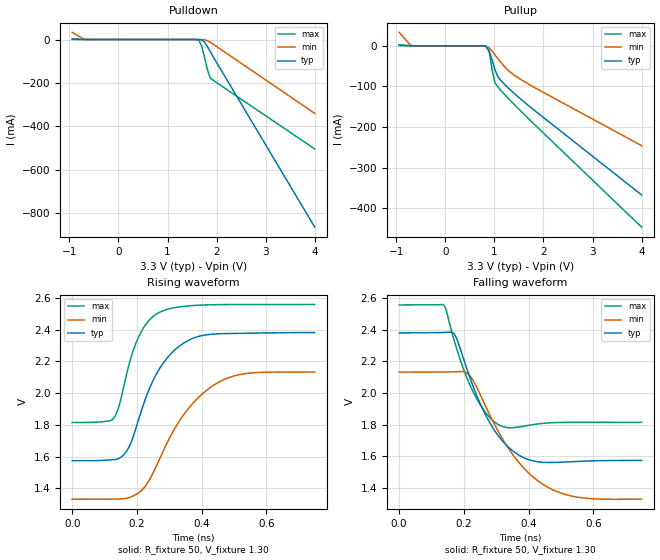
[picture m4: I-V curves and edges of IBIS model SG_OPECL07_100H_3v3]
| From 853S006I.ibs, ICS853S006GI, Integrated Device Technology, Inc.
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[Model] SG_OPECL07_100H_3v3
Model_type   Output_ECL
Polarity   Non-Inverting
|   typ   min   max
C_comp   2pF   1.5pF   2.5pF
Vmeas = 2.0V
Rref = 50
Cref = 0
Vref = 1.3V
|   typ   min   max
[Voltage range]   3.3V   3.135V   3.465V
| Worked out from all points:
|   rising waveform, R_fixture 50, V_fixture 1.30: 20-80 % time 103ps typ, 142ps min, 69.2ps max; typ from 1.57 V to 2.38 V
|   falling waveform, R_fixture 50, V_fixture 1.30: 20-80 % time 106ps typ, 148ps min, 80.1ps max; typ from 2.38 V to 1.57 V
[Pulldown]
|Voltage   I (typ)   I (min)   I (max)
-941.5mV  2.604mA    33.15mA    41.3uA
-711.7mV  75.61uA    1.458mA    617.8nA
-654.2mV  8.078uA    226.5uA    35.41nA
1.587V    -35.94uA   -8.024uA   -361.8uA
1.644V    -319.1uA   -49.68uA   -5.269mA
1.702V    -2.559mA   -299.7uA   -35.21mA
1.759V    -13.03mA   -1.595mA   -87.58mA
1.817V    -33.44mA   -5.834mA   -142.5mA
1.874V    -56.95mA   -13.21mA   -177.7mA
4V        -864.8mA   -340.5mA   -504.4mA
[Pullup]
|Voltage   I (typ)   I (min)   I (max)
-941.5mV  2.604mA    33.15mA    41.3uA
-711.7mV  75.61uA    1.458mA    617.8nA
-654.2mV  8.078uA    226.5uA    35.4nA
839.7mV   -3.036mA   -1.503mA   -1.469mA
897.2mV   -14.72mA   -5.72mA    -16.07mA
954.6mV   -36.13mA   -13.37mA   -60.49mA
1.012V    -59.55mA   -22.45mA   -91.49mA
1.07V     -75.46mA   -31.59mA   -101.1mA
1.127V    -84.8mA    -40.3mA    -109.3mA
1.357V    -112.3mA   -68.13mA   -138.8mA
1.644V    -142.1mA   -90.7mA    -173.4mA
4V        -367.2mA   -245.9mA   -446.5mA
[Ramp]
|   typ   min   max
dV/dt_r   0.646/0.16n   0.641/0.214n   0.595/0.111n
dV/dt_f   0.661/0.16n   0.648/0.22n   0.625/0.123n
R_load =   50.0000
[Rising Waveform]
R_fixture = 50
V_fixture = 1.30   | VCC_typ - 2V
V_fixture_max = 1.465   | VCC_max - 2V
V_fixture_min = 1.135   | VCC_min - 2V
C_fixture = 0.0p
| Time   typ   min   max
0s        1.573V     1.331V     1.814V
122.4ps   1.579V     1.331V     1.831V
140.4ps   1.585V     1.332V     1.893V
159.2ps   1.612V     1.334V     2.042V
207.2ps   1.848V     1.374V     2.364V
271.8ps   2.161V     1.594V     2.511V
354.4ps   2.327V     1.891V     2.549V
452.7ps   2.373V     2.068V     2.557V
545.8ps   2.377V     2.125V     2.558V
749.2ps   2.381V     2.132V     2.558V
[Falling Waveform]
R_fixture = 50
V_fixture = 1.30   | VCC_typ - 2V
V_fixture_max = 1.465   | VCC_max - 2V
V_fixture_min = 1.135   | VCC_min - 2V
C_fixture = 0.0p
| Time   typ   min   max
0s        2.381V     2.133V     2.558V
137.4ps   2.384V     2.133V     2.558V
168.9ps   2.377V     2.134V     2.341V
220.7ps   2.085V     2.103V     2.041V
266.5ps   1.863V     1.919V     1.877V
311.6ps   1.715V     1.737V     1.794V
385.1ps   1.59V      1.524V     1.79V
476.7ps   1.56V      1.385V     1.812V
575.1ps   1.569V     1.333V     1.814V
749.2ps   1.573V     1.327V     1.814V
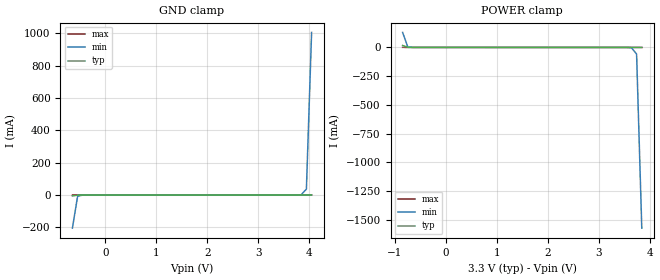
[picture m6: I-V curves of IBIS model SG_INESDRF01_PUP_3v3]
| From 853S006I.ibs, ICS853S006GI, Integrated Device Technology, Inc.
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[Model] SG_INESDRF01_PUP_3v3
Model_type   Input
Polarity   Non-Inverting
Vinl = 0.8V
Vinh = 2.0V
|   typ   min   max
C_comp   2pF   1.5pF   2.5pF
|   typ   min   max
[Voltage range]  3.3V   3.135V   3.465V
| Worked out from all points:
|   GND clamp passes 1 mA (typ) near -0.56 V on its own axis
|   POWER clamp passes 1 mA (typ) near -0.75 V on its own axis
[GND_clamp]
|Voltage   I(Typ)   I(Min)   I(Max)
-646.4mV  -5.84mA    -204.9mA   -106.2uA
-544.3mV  -195.2uA   -7.586mA   -84.59uA
-442.3mV  -85uA      -357.4uA   -80.69uA
3.844V    87.13uA    1.444mA    78.35uA
3.946V    97.02uA    36.95mA    82.14uA
4.048V    411.2uA    1.006A     85.93uA
[POWER_clamp]
|Voltage   I(Typ)   I(Min)   I(Max)
-850.5mV  16.89mA    131mA      714.6uA
-748.5mV  411.2uA    4.891mA    95.9uA
-646.4mV  97.02uA    266.8uA    88.29uA
3.64V     -78.96uA   -2.196mA   -70.77uA
3.742V    -85uA      -57.73mA   -74.56uA
3.844V    -195.2uA   -1.574A    -78.35uA
